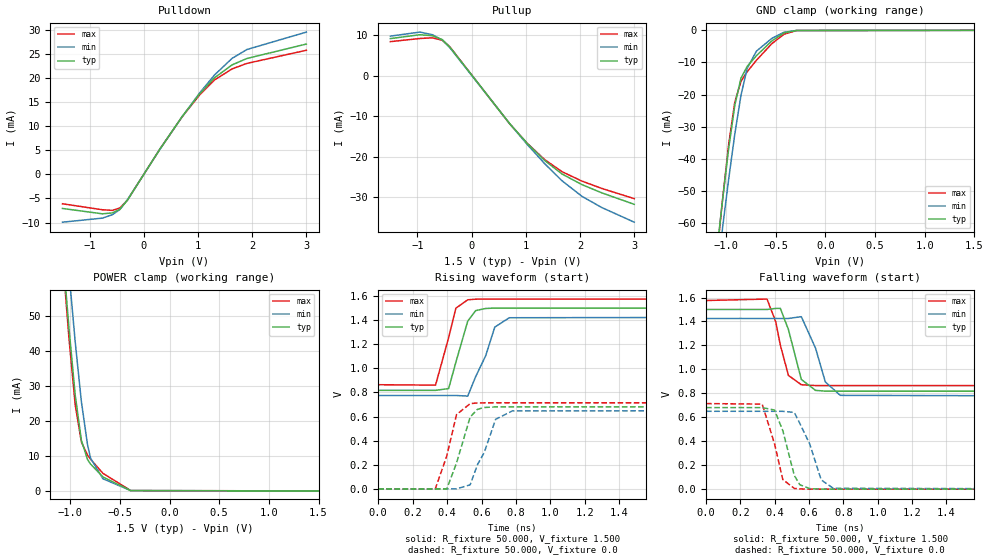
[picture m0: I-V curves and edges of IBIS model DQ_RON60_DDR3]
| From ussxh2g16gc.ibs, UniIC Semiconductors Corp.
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|   Model DQ_RON60_DDR3
[Model] DQ_RON60_DDR3
Model_type I/O
Vinl =  0.615V
Vinh =  0.885V
Vmeas =  0.750V
Rref =  50.000
Vref =  0.750V
C_comp   0.966pF   0.965pF   0.967pF
[Model Spec]
Vinh   0.885V   0.847V   0.922V
Vinl   0.615V   0.577V   0.652V
Vmeas   0.750V   0.712V   0.787V
Vref   0.750V   0.712V   0.787V
Rref   50.000   NA   NA
[Temperature Range]   25.000   95.000   0.0
[Voltage Range]   1.500V   1.425V   1.575V
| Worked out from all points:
|   slope of the pulldown table from 0 to 0.225 V, typ, clamps not added: 56.5 ohm
|   slope of the pullup table from 0 to 0.225 V, typ, clamps not added: 57.4 ohm
|   GND clamp passes 1 mA (typ) near -0.43 V on its own axis
|   POWER clamp passes 1 mA (typ) near -0.52 V on its own axis
|   rising waveform, R_fixture 50.000, V_fixture 1.500: 20-80 % time 81.6ps typ, 103ps min, 71ps max; typ from 0.818 V to 1.5 V
|   rising waveform, R_fixture 50.000, V_fixture 0.0: 20-80 % time 84.5ps typ, 106ps min, 74.9ps max; typ from 0 V to 0.681 V
|   falling waveform, R_fixture 50.000, V_fixture 1.500: 20-80 % time 71.8ps typ, 86.9ps min, 65.2ps max; typ from 1.5 V to 0.818 V
|   falling waveform, R_fixture 50.000, V_fixture 0.0: 20-80 % time 76.4ps typ, 97.3ps min, 66.7ps max; typ from 0.681 V to 0 V
[Pulldown]
|Voltage   I(typ)   I(min)   I(max)
-1.5V     -7.077mA   -9.924mA   -6.103mA
-764mV    -8.187mA   -9.081mA   -7.347mA
-580mV    -7.998mA   -8.377mA   -7.472mA
-442mV    -7.252mA   -7.298mA   -6.985mA
-304mV    -5.41mA    -5.318mA   -5.388mA
294mV     5.178mA    5.104mA    5.182mA
708mV     11.98mA    11.95mA    11.91mA
1.03V     16.67mA    16.85mA    16.45mA
1.306V    20.02mA    20.6mA     19.56mA
1.628V    22.68mA    24.03mA    21.85mA
1.904V    24.02mA    25.88mA    23mA
3V        27.01mA    29.49mA    25.72mA
[Pullup]
|Voltage   I(typ)   I(min)   I(max)
-1.5V     9.205mA    9.811mA    8.45mA
-956mV    10.16mA    10.81mA    9.228mA
-726mV    9.917mA    10.17mA    9.391mA
-542mV    8.946mA    8.844mA    8.795mA
-404mV    7.122mA    6.979mA    7.188mA
700mV     -11.77mA   -11.79mA   -11.84mA
1.022V    -16.63mA   -16.89mA   -16.61mA
1.344V    -20.88mA   -21.65mA   -20.65mA
1.666V    -24.23mA   -25.9mA    -23.66mA
2.034V    -26.86mA   -29.75mA   -25.99mA
2.402V    -28.9mA    -32.53mA   -27.81mA
3V        -31.73mA   -36.14mA   -30.33mA
[GND_clamp]
|Voltage   I(typ)   I(min)   I(max)
-1.5V     -194.2mA   -188.5mA   -209.3mA
-1.066V   -61.52mA   -69.48mA   -62.16mA
-1.035V   -52.91mA   -61.57mA   -52.74mA
-973mV    -36.75mA   -46.31mA   -35.46mA
-911mV    -23.25mA   -32.21mA   -22.31mA
-849mV    -14.87mA   -20.19mA   -15.86mA
-787mV    -11.24mA   -11.84mA   -12.89mA
-694mV    -7.909mA   -6.483mA   -9.328mA
-539mV    -3.3mA     -2.519mA   -4.154mA
-415mV    -796.6uA   -587.2uA   -1.2mA
-291mV    -42.28uA   -42.7uA    -83.65uA
1.5V      0A         0A         0A
[POWER_clamp]
|Voltage   I(typ)   I(min)   I(max)
-1.5V     238.9mA    243.4mA    249.4mA
-1.104V   79.29mA    94.04mA    78.24mA
-1.073V   67.84mA    83.12mA    66.04mA
-1.042V   56.75mA    72.44mA    54.3mA
-1.011V   46.15mA    62.05mA    43.22mA
-949mV    27.34mA    42.47mA    24.53mA
-887mV    14.41mA    25.48mA    13.98mA
-825mV    8.956mA    13.13mA    10.21mA
-794mV    7.645mA    9.305mA    9.033mA
-670mV    3.99mA     3.471mA    5.018mA
-391mV    72.25uA    105.7uA    112.3uA
1.5V      0A         0A         0A
[Ramp]
| variable   typ   min   max
dV/dt_r   0.409/84.474p   0.390/0.106n   0.429/74.925p
dV/dt_f   0.409/71.683p   0.390/86.888p   0.426/65.445p
R_load = 50.000
[Rising Waveform]
R_fixture= 50.000
V_fixture= 1.500
V_fixture_min= 1.425
V_fixture_max= 1.575
|time   V(typ)   V(min)   V(max)
0s        817.6mV    774.9mV    864.4mV
333ps     817.5mV    774.9mV    860.8mV
409ps     832.3mV    774.9mV    1.254V
451ps     1.05V      775.1mV    1.499V
520ps     1.392V     770.1mV    1.569V
566ps     1.479V     931.2mV    1.574V
624ps     1.497V     1.104V     1.575V
677ps     1.5V       1.342V     1.575V
761ps     1.5V       1.42V      1.575V
3ns       1.5V       1.425V     1.575V
[Rising Waveform]
R_fixture= 50.000
V_fixture= 0.0
V_fixture_min= 0.0
V_fixture_max= 0.0
|time   V(typ)   V(min)   V(max)
0s        223nV      1.468uV    252.9nV
331ps     -38.28uV   3.821uV    -2.24mV
398ps     -1.264mV   -6.258uV   271.9mV
455ps     214.8mV    185.2uV    616.7mV
534ps     596.1mV    33.9mV     707.6mV
577ps     660.6mV    202.4mV    712.9mV
616ps     675.4mV    302.3mV    714.1mV
682ps     680.4mV    577.5mV    714.5mV
779ps     681mV      646.9mV    714.5mV
3ns       681.1mV    650.1mV    714.5mV
[Falling Waveform]
R_fixture= 50.000
V_fixture= 1.500
V_fixture_min= 1.425
V_fixture_max= 1.575
|time   V(typ)   V(min)   V(max)
0s        1.5V       1.425V     1.575V
355ps     1.5V       1.425V     1.587V
406ps     1.509V     1.425V     1.397V
433ps     1.509V     1.425V     1.201V
480ps     1.332V     1.425V     949.6mV
555ps     916.2mV    1.44V      871.9mV
638ps     824.6mV    1.177V     864.9mV
695ps     818.6mV    895.4mV    864.5mV
782ps     817.6mV    783.2mV    864.4mV
3ns       817.6mV    774.9mV    864.4mV
[Falling Waveform]
R_fixture= 50.000
V_fixture= 0.0
V_fixture_min= 0.0
V_fixture_max= 0.0
|time   V(typ)   V(min)   V(max)
0s        681.1mV    650.1mV    714.5mV
327ps     681mV      650mV      710.1mV
399ps     660.4mV    650mV      378.5mV
447ps     489.2mV    649.9mV    80.81mV
514ps     115mV      640.8mV    6.568mV
546ps     37.14mV    550mV      1.974mV
604ps     4.596mV    377mV      213.9uV
671ps     405.4uV    77.49mV    16.47uV
741ps     30.4uV     7.48mV     1.411uV
3ns       258.2nV    1.483uV    307.7nV
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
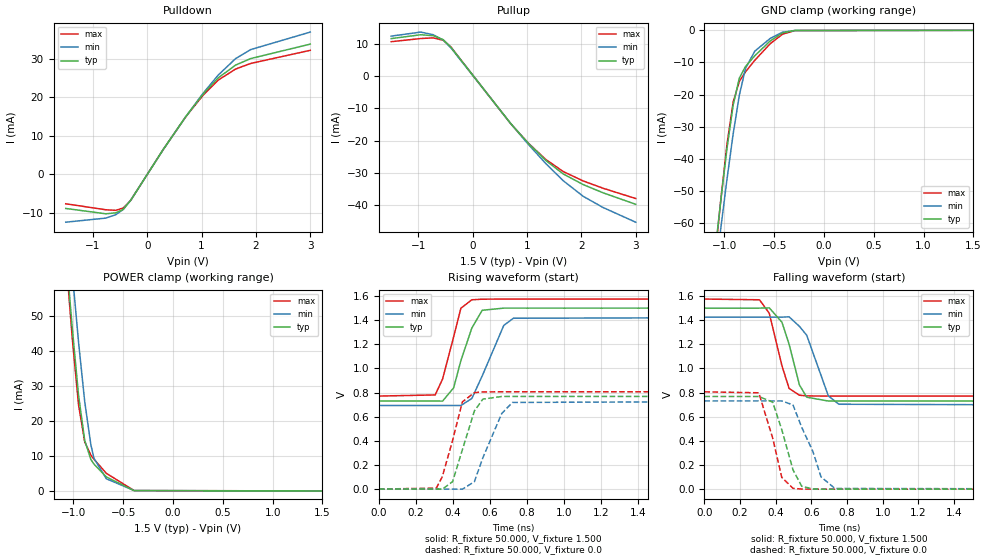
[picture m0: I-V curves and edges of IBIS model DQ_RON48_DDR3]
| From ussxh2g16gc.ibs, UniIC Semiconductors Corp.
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|   Model DQ_RON48_DDR3
[Model] DQ_RON48_DDR3
Model_type I/O
Vinl =  0.615V
Vinh =  0.885V
Vmeas =  0.750V
Rref =  50.000
Vref =  0.750V
C_comp   0.966pF   0.965pF   0.967pF
[Model Spec]
Vinh   0.885V   0.847V   0.922V
Vinl   0.615V   0.577V   0.652V
Vmeas   0.750V   0.712V   0.787V
Vref   0.750V   0.712V   0.787V
Rref   50.000   NA   NA
[Temperature Range]   25.000   95.000   0.0
[Voltage Range]   1.500V   1.425V   1.575V
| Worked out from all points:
|   slope of the pulldown table from 0 to 0.225 V, typ, clamps not added: 45.2 ohm
|   slope of the pullup table from 0 to 0.225 V, typ, clamps not added: 45.9 ohm
|   GND clamp passes 1 mA (typ) near -0.43 V on its own axis
|   POWER clamp passes 1 mA (typ) near -0.52 V on its own axis
|   rising waveform, R_fixture 50.000, V_fixture 1.500: 20-80 % time 90ps typ, 117ps min, 77.5ps max; typ from 0.73 V to 1.5 V
|   rising waveform, R_fixture 50.000, V_fixture 0.0: 20-80 % time 91.1ps typ, 115ps min, 80.3ps max; typ from 0 V to 0.768 V
|   falling waveform, R_fixture 50.000, V_fixture 1.500: 20-80 % time 83.9ps typ, 104ps min, 75.5ps max; typ from 1.5 V to 0.73 V
|   falling waveform, R_fixture 50.000, V_fixture 0.0: 20-80 % time 90.1ps typ, 114ps min, 78.3ps max; typ from 0.768 V to 0 V
[Pulldown]
|Voltage   I(typ)   I(min)   I(max)
-1.5V     -8.855mA   -12.42mA   -7.638mA
-764mV    -10.24mA   -11.36mA   -9.193mA
-580mV    -10mA      -10.48mA   -9.347mA
-442mV    -9.069mA   -9.126mA   -8.736mA
-304mV    -6.766mA   -6.65mA    -6.738mA
294mV     6.475mA    6.383mA    6.481mA
708mV     14.98mA    14.94mA    14.9mA
1.03V     20.85mA    21.08mA    20.57mA
1.306V    25.04mA    25.76mA    24.46mA
1.628V    28.37mA    30.06mA    27.34mA
1.904V    30.05mA    32.38mA    28.78mA
3V        33.8mA     36.92mA    32.19mA
[Pullup]
|Voltage   I(typ)   I(min)   I(max)
-1.5V     11.52mA    12.28mA    10.56mA
-956mV    12.71mA    13.53mA    11.54mA
-726mV    12.41mA    12.72mA    11.74mA
-542mV    11.19mA    11.06mA    11mA
-404mV    8.909mA    8.73mA     8.986mA
700mV     -14.73mA   -14.75mA   -14.8mA
1.022V    -20.8mA    -21.12mA   -20.76mA
1.344V    -26.12mA   -27.08mA   -25.81mA
1.666V    -30.31mA   -32.4mA    -29.57mA
2.034V    -33.61mA   -37.23mA   -32.48mA
2.402V    -36.16mA   -40.71mA   -34.75mA
3V        -39.7mA    -45.23mA   -37.91mA
[GND_clamp]
|Voltage   I(typ)   I(min)   I(max)
-1.5V     -194.2mA   -188.5mA   -209.3mA
-1.066V   -61.52mA   -69.48mA   -62.16mA
-1.035V   -52.91mA   -61.57mA   -52.74mA
-973mV    -36.75mA   -46.31mA   -35.46mA
-911mV    -23.25mA   -32.21mA   -22.31mA
-849mV    -14.87mA   -20.19mA   -15.86mA
-787mV    -11.24mA   -11.84mA   -12.89mA
-694mV    -7.909mA   -6.483mA   -9.328mA
-539mV    -3.3mA     -2.519mA   -4.154mA
-415mV    -796.6uA   -587.2uA   -1.2mA
-291mV    -42.28uA   -42.7uA    -83.65uA
1.5V      0A         0A         0A
[POWER_clamp]
|Voltage   I(typ)   I(min)   I(max)
-1.5V     238.9mA    243.4mA    249.4mA
-1.104V   79.29mA    94.04mA    78.24mA
-1.073V   67.84mA    83.12mA    66.04mA
-1.042V   56.75mA    72.44mA    54.3mA
-1.011V   46.15mA    62.05mA    43.22mA
-949mV    27.34mA    42.47mA    24.53mA
-887mV    14.41mA    25.48mA    13.98mA
-825mV    8.956mA    13.13mA    10.21mA
-794mV    7.645mA    9.305mA    9.033mA
-670mV    3.99mA     3.471mA    5.018mA
-391mV    72.25uA    105.7uA    112.3uA
1.5V      0A         0A         0A
[Ramp]
| variable   typ   min   max
dV/dt_r   0.461/90.981p   0.439/0.115n   0.484/80.401p
dV/dt_f   0.462/83.868p   0.439/0.104n   0.482/75.519p
R_load = 50.000
[Rising Waveform]
R_fixture= 50.000
V_fixture= 1.500
V_fixture_min= 1.425
V_fixture_max= 1.575
|time   V(typ)   V(min)   V(max)
0s        729.8mV    693mV      771mV
304ps     729.8mV    693mV      780.3mV
344ps     729.1mV    693mV      912.4mV
404ps     839.9mV    693mV      1.263V
443ps     1.065V     692.6mV    1.499V
502ps     1.334V     750.7mV    1.569V
558ps     1.482V     937mV      1.574V
675ps     1.5V       1.357V     1.575V
727ps     1.5V       1.416V     1.575V
3ns       1.5V       1.425V     1.575V
[Rising Waveform]
R_fixture= 50.000
V_fixture= 0.0
V_fixture_min= 0.0
V_fixture_max= 0.0
|time   V(typ)   V(min)   V(max)
0s        208.5nV    1.321uV    242.4nV
310ps     62.31uV    5.681uV    8.055mV
342ps     -657.9uV   1.334uV    100.5mV
398ps     60.93mV    18.37uV    402.5mV
451ps     326mV      -727.6uV   723.3mV
516ps     647.3mV    61.34mV    799.4mV
562ps     745.7mV    260.6mV    805.2mV
664ps     767.4mV    626.9mV    806.5mV
722ps     767.9mV    718.1mV    806.5mV
3ns       767.9mV    731.2mV    806.5mV
[Falling Waveform]
R_fixture= 50.000
V_fixture= 1.500
V_fixture_min= 1.425
V_fixture_max= 1.575
|time   V(typ)   V(min)   V(max)
0s        1.5V       1.425V     1.575V
309ps     1.5V       1.425V     1.569V
364ps     1.502V     1.425V     1.457V
435ps     1.383V     1.425V     1.022V
475ps     1.201V     1.428V     834.8mV
533ps     863.9mV    1.349V     778.5mV
574ps     762mV      1.275V     772.6mV
695ps     730.2mV    772.9mV    771mV
754ps     729.9mV    703.6mV    771mV
3ns       729.8mV    693mV      771mV
[Falling Waveform]
R_fixture= 50.000
V_fixture= 0.0
V_fixture_min= 0.0
V_fixture_max= 0.0
|time   V(typ)   V(min)   V(max)
0s        767.9mV    731.2mV    806.5mV
305ps     767.8mV    731.2mV    798.4mV
383ps     721.1mV    731.2mV    423.3mV
434ps     493.2mV    731.1mV    97.5mV
497ps     159.9mV    697.6mV    6.883mV
546ps     23.8mV     511.8mV    853.2uV
609ps     1.846mV    310.2mV    55.42uV
654ps     294.6uV    102mV      8.177uV
732ps     11.67uV    5.786mV    632.1nV
3ns       217.6nV    1.311uV    319.8nV
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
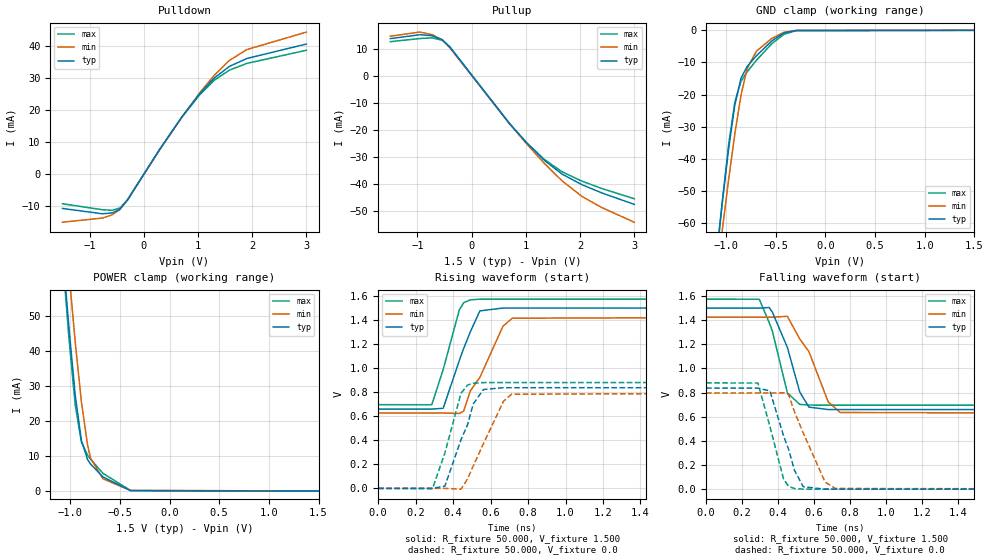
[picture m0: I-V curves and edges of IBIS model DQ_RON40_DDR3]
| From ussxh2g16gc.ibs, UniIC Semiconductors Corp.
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|   Model DQ_RON40_DDR3
[Model] DQ_RON40_DDR3
Model_type I/O
Vinl =  0.615V
Vinh =  0.885V
Vmeas =  0.750V
Rref =  50.000
Vref =  0.750V
C_comp   0.966pF   0.965pF   0.967pF
[Model Spec]
Vinh   0.885V   0.847V   0.922V
Vinl   0.615V   0.577V   0.652V
Vmeas   0.750V   0.712V   0.787V
Vref   0.750V   0.712V   0.787V
Rref   50.000   NA   NA
[Temperature Range]   25.000   95.000   0.0
[Voltage Range]   1.500V   1.425V   1.575V
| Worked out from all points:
|   slope of the pulldown table from 0 to 0.225 V, typ, clamps not added: 37.7 ohm
|   slope of the pullup table from 0 to 0.225 V, typ, clamps not added: 38.3 ohm
|   GND clamp passes 1 mA (typ) near -0.43 V on its own axis
|   POWER clamp passes 1 mA (typ) near -0.52 V on its own axis
|   rising waveform, R_fixture 50.000, V_fixture 1.500: 20-80 % time 119ps typ, 161ps min, 98.6ps max; typ from 0.659 V to 1.5 V
|   rising waveform, R_fixture 50.000, V_fixture 0.0: 20-80 % time 109ps typ, 148ps min, 89.9ps max; typ from 0 V to 0.837 V
|   falling waveform, R_fixture 50.000, V_fixture 1.500: 20-80 % time 112ps typ, 151ps min, 92.4ps max; typ from 1.5 V to 0.659 V
|   falling waveform, R_fixture 50.000, V_fixture 0.0: 20-80 % time 107ps typ, 141ps min, 91.1ps max; typ from 0.837 V to 0 V
[Pulldown]
|Voltage   I(typ)   I(min)   I(max)
-1.5V     -10.61mA   -14.88mA   -9.148mA
-764mV    -12.27mA   -13.61mA   -11.01mA
-580mV    -11.99mA   -12.56mA   -11.2mA
-442mV    -10.87mA   -10.94mA   -10.47mA
-304mV    -8.107mA   -7.968mA   -8.072mA
294mV     7.758mA    7.648mA    7.763mA
708mV     17.95mA    17.9mA     17.85mA
1.03V     24.98mA    25.25mA    24.65mA
1.306V    30mA       30.86mA    29.3mA
1.582V    33.55mA    35.4mA     32.38mA
1.904V    35.99mA    38.77mA    34.47mA
3V        40.48mA    44.19mA    38.54mA
[Pullup]
|Voltage   I(typ)   I(min)   I(max)
-1.5V     13.8mA     14.7mA     12.67mA
-956mV    15.23mA    16.21mA    13.83mA
-726mV    14.86mA    15.24mA    14.08mA
-542mV    13.41mA    13.25mA    13.18mA
-404mV    10.67mA    10.46mA    10.77mA
700mV     -17.64mA   -17.67mA   -17.74mA
1.022V    -24.91mA   -25.3mA    -24.88mA
1.344V    -31.28mA   -32.43mA   -30.93mA
1.666V    -36.29mA   -38.79mA   -35.44mA
2.034V    -40.23mA   -44.56mA   -38.92mA
2.402V    -43.28mA   -48.71mA   -41.65mA
3V        -47.51mA   -54.1mA    -45.43mA
[GND_clamp]
|Voltage   I(typ)   I(min)   I(max)
-1.5V     -194.2mA   -188.5mA   -209.3mA
-1.066V   -61.52mA   -69.48mA   -62.16mA
-1.035V   -52.91mA   -61.57mA   -52.74mA
-973mV    -36.75mA   -46.31mA   -35.46mA
-911mV    -23.25mA   -32.21mA   -22.31mA
-849mV    -14.87mA   -20.19mA   -15.86mA
-787mV    -11.24mA   -11.84mA   -12.89mA
-694mV    -7.909mA   -6.483mA   -9.328mA
-539mV    -3.3mA     -2.519mA   -4.154mA
-415mV    -796.6uA   -587.2uA   -1.2mA
-291mV    -42.28uA   -42.7uA    -83.65uA
1.5V      0A         0A         0A
[POWER_clamp]
|Voltage   I(typ)   I(min)   I(max)
-1.5V     238.9mA    243.4mA    249.4mA
-1.104V   79.29mA    94.04mA    78.24mA
-1.073V   67.84mA    83.12mA    66.04mA
-1.042V   56.75mA    72.44mA    54.3mA
-1.011V   46.15mA    62.05mA    43.22mA
-949mV    27.34mA    42.47mA    24.53mA
-887mV    14.41mA    25.48mA    13.98mA
-825mV    8.956mA    13.13mA    10.21mA
-794mV    7.645mA    9.305mA    9.033mA
-670mV    3.99mA     3.471mA    5.018mA
-391mV    72.25uA    105.7uA    112.3uA
1.5V      0A         0A         0A
[Ramp]
| variable   typ   min   max
dV/dt_r   0.502/0.108n   0.478/0.148n   0.528/89.963p
dV/dt_f   0.504/0.112n   0.479/0.151n   0.527/92.509p
R_load = 50.000
[Rising Waveform]
R_fixture= 50.000
V_fixture= 1.500
V_fixture_min= 1.425
V_fixture_max= 1.575
|time   V(typ)   V(min)   V(max)
0s        659.5mV    627.1mV    696.2mV
286ps     659.5mV    627.1mV    695.9mV
347ps     666.4mV    627.1mV    989.2mV
433ps     1.064V     623mV      1.485V
456ps     1.163V     642.3mV    1.544V
492ps     1.303V     811.2mV    1.569V
543ps     1.477V     924.1mV    1.574V
666ps     1.5V       1.349V     1.575V
716ps     1.5V       1.416V     1.575V
3ns       1.5V       1.425V     1.575V
[Rising Waveform]
R_fixture= 50.000
V_fixture= 0.0
V_fixture_min= 0.0
V_fixture_max= 0.0
|time   V(typ)   V(min)   V(max)
0s        197.4nV    1.203uV    234.8nV
290ps     75.71uV    3.746uV    -1.937mV
356ps     18.73mV    -53.76uV   294.2mV
442ps     404.8mV    -6.628mV   791.4mV
477ps     529.5mV    78.62mV    859.6mV
507ps     701.2mV    185mV      874.5mV
562ps     822.6mV    372.6mV    879.9mV
669ps     837.3mV    725.3mV    880.5mV
712ps     837.4mV    783.4mV    880.5mV
3ns       837.4mV    796.3mV    880.5mV
[Falling Waveform]
R_fixture= 50.000
V_fixture= 1.500
V_fixture_min= 1.425
V_fixture_max= 1.575
|time   V(typ)   V(min)   V(max)
0s        1.5V       1.425V     1.575V
296ps     1.5V       1.425V     1.573V
351ps     1.505V     1.425V     1.38V
369ps     1.465V     1.425V     1.307V
452ps     1.174V     1.432V     797mV
521ps     804.1mV    1.244V     702.5mV
572ps     679.7mV    1.139V     697mV
679ps     659.7mV    722.9mV    696.2mV
746ps     659.5mV    635.2mV    696.2mV
3ns       659.5mV    627.1mV    696.2mV
[Falling Waveform]
R_fixture= 50.000
V_fixture= 0.0
V_fixture_min= 0.0
V_fixture_max= 0.0
|time   V(typ)   V(min)   V(max)
0s        837.4mV    796.3mV    880.5mV
288ps     837.3mV    796.3mV    879.5mV
355ps     813.9mV    796.3mV    518.4mV
431ps     440.7mV    797.8mV    83.25mV
459ps     329.6mV    783.9mV    23.17mV
491ps     158.4mV    642.5mV    5.125mV
540ps     19.92mV    466.5mV    518.5uV
662ps     87.94uV    58.13mV    1.85uV
720ps     6.634uV    5.563mV    438.5nV
3ns       226.3nV    1.164uV    278.6nV
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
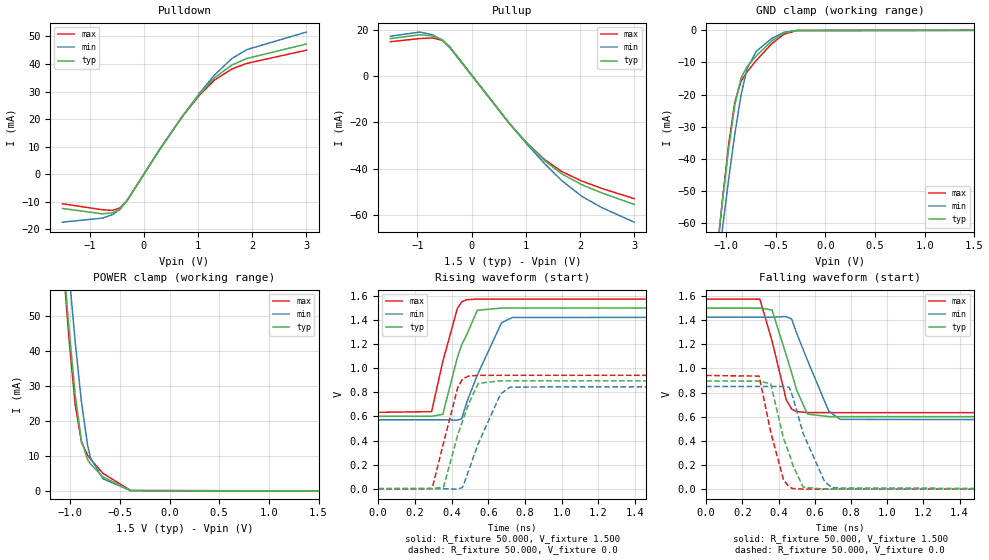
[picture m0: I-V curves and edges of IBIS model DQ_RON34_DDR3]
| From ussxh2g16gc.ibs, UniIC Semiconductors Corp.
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|   Model DQ_RON34_DDR3
[Model] DQ_RON34_DDR3
Model_type I/O
Vinl =  0.615V
Vinh =  0.885V
Vmeas =  0.750V
Rref =  50.000
Vref =  0.750V
C_comp   0.966pF   0.965pF   0.967pF
[Model Spec]
Vinh   0.885V   0.847V   0.922V
Vinl   0.615V   0.577V   0.652V
Vmeas   0.750V   0.712V   0.787V
Vref   0.750V   0.712V   0.787V
Rref   50.000   NA   NA
[Temperature Range]   25.000   95.000   0.0
[Voltage Range]   1.500V   1.425V   1.575V
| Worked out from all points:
|   slope of the pulldown table from 0 to 0.225 V, typ, clamps not added: 32.3 ohm
|   slope of the pullup table from 0 to 0.225 V, typ, clamps not added: 32.8 ohm
|   GND clamp passes 1 mA (typ) near -0.43 V on its own axis
|   POWER clamp passes 1 mA (typ) near -0.52 V on its own axis
|   rising waveform, R_fixture 50.000, V_fixture 1.500: 20-80 % time 114ps typ, 151ps min, 95.9ps max; typ from 0.601 V to 1.5 V
|   rising waveform, R_fixture 50.000, V_fixture 0.0: 20-80 % time 108ps typ, 142ps min, 91.5ps max; typ from 0 V to 0.896 V
|   falling waveform, R_fixture 50.000, V_fixture 1.500: 20-80 % time 111ps typ, 145ps min, 95.3ps max; typ from 1.5 V to 0.601 V
|   falling waveform, R_fixture 50.000, V_fixture 0.0: 20-80 % time 102ps typ, 132ps min, 88.3ps max; typ from 0.896 V to 0 V
[Pulldown]
|Voltage   I(typ)   I(min)   I(max)
-1.5V     -12.39mA   -17.36mA   -10.68mA
-764mV    -14.32mA   -15.88mA   -12.85mA
-580mV    -13.99mA   -14.65mA   -13.07mA
-442mV    -12.68mA   -12.76mA   -12.21mA
-304mV    -9.452mA   -9.291mA   -9.412mA
294mV     9.046mA    8.917mA    9.052mA
708mV     20.93mA    20.87mA    20.81mA
1.03V     29.13mA    29.45mA    28.74mA
1.306V    34.98mA    35.99mA    34.17mA
1.628V    39.63mA    41.99mA    38.19mA
1.904V    41.98mA    45.21mA    40.21mA
3V        47.22mA    51.54mA    44.96mA
[Pullup]
|Voltage   I(typ)   I(min)   I(max)
-1.5V     16.11mA    17.15mA    14.78mA
-956mV    17.77mA    18.93mA    16.14mA
-726mV    17.35mA    17.79mA    16.42mA
-542mV    15.64mA    15.46mA    15.37mA
-404mV    12.45mA    12.2mA     12.56mA
700mV     -20.57mA   -20.61mA   -20.68mA
1.022V    -29.06mA   -29.51mA   -29.01mA
1.344V    -36.49mA   -37.83mA   -36.06mA
1.666V    -42.33mA   -45.25mA   -41.31mA
2.034V    -46.94mA   -51.98mA   -45.37mA
2.402V    -50.49mA   -56.83mA   -48.55mA
3V        -55.43mA   -63.11mA   -52.95mA
[GND_clamp]
|Voltage   I(typ)   I(min)   I(max)
-1.5V     -194.2mA   -188.5mA   -209.3mA
-1.066V   -61.52mA   -69.48mA   -62.16mA
-1.035V   -52.91mA   -61.57mA   -52.74mA
-973mV    -36.75mA   -46.31mA   -35.46mA
-911mV    -23.25mA   -32.21mA   -22.31mA
-849mV    -14.87mA   -20.19mA   -15.86mA
-787mV    -11.24mA   -11.84mA   -12.89mA
-694mV    -7.909mA   -6.483mA   -9.328mA
-539mV    -3.3mA     -2.519mA   -4.154mA
-415mV    -796.6uA   -587.2uA   -1.2mA
-291mV    -42.28uA   -42.7uA    -83.65uA
1.5V      0A         0A         0A
[POWER_clamp]
|Voltage   I(typ)   I(min)   I(max)
-1.5V     238.9mA    243.4mA    249.4mA
-1.104V   79.29mA    94.04mA    78.24mA
-1.073V   67.84mA    83.12mA    66.04mA
-1.042V   56.75mA    72.44mA    54.3mA
-1.011V   46.15mA    62.05mA    43.22mA
-949mV    27.34mA    42.47mA    24.53mA
-887mV    14.41mA    25.48mA    13.98mA
-825mV    8.956mA    13.13mA    10.21mA
-794mV    7.645mA    9.305mA    9.033mA
-670mV    3.99mA     3.471mA    5.018mA
-391mV    72.25uA    105.7uA    112.3uA
1.5V      0A         0A         0A
[Ramp]
| variable   typ   min   max
dV/dt_r   0.537/0.108n   0.510/0.142n   0.565/91.452p
dV/dt_f   0.539/0.111n   0.512/0.145n   0.565/95.483p
R_load = 50.000
[Rising Waveform]
R_fixture= 50.000
V_fixture= 1.500
V_fixture_min= 1.425
V_fixture_max= 1.575
|time   V(typ)   V(min)   V(max)
0s        601.1mV    572.4mV    634.1mV
291ps     601.2mV    572.5mV    640mV
352ps     617.7mV    572.4mV    1.056V
431ps     1.086V     569.2mV    1.495V
455ps     1.195V     580mV      1.552V
484ps     1.284V     724.4mV    1.57V
540ps     1.482V     942.2mV    1.575V
672ps     1.5V       1.378V     1.575V
731ps     1.5V       1.422V     1.575V
3ns       1.5V       1.425V     1.575V
[Rising Waveform]
R_fixture= 50.000
V_fixture= 0.0
V_fixture_min= 0.0
V_fixture_max= 0.0
|time   V(typ)   V(min)   V(max)
0s        187.9nV    1.105uV    228nV
294ps     143.6uV    5.374uV    1.426mV
356ps     13.75mV    -62.73uV   378.2mV
434ps     449mV      -4.096mV   842.3mV
460ps     562.2mV    11.22mV    911.5mV
494ps     708.3mV    155mV      935.5mV
546ps     875.3mV    377.4mV    941.3mV
667ps     895.5mV    787.1mV    941.9mV
719ps     895.6mV    844.2mV    941.9mV
3ns       895.6mV    850.7mV    941.9mV
[Falling Waveform]
R_fixture= 50.000
V_fixture= 1.500
V_fixture_min= 1.425
V_fixture_max= 1.575
|time   V(typ)   V(min)   V(max)
0s        1.5V       1.425V     1.575V
297ps     1.5V       1.425V     1.574V
364ps     1.485V     1.425V     1.229V
443ps     1.109V     1.43V      739.4mV
473ps     960.7mV    1.409V     663mV
500ps     821.7mV    1.292V     642.6mV
560ps     622mV      1.067V     634.7mV
678ps     601.2mV    645.3mV    634.1mV
741ps     601.1mV    578.3mV    634.1mV
3ns       601.1mV    572.4mV    634.1mV
[Falling Waveform]
R_fixture= 50.000
V_fixture= 0.0
V_fixture_min= 0.0
V_fixture_max= 0.0
|time   V(typ)   V(min)   V(max)
0s        895.6mV    850.7mV    941.9mV
293ps     895.3mV    850.7mV    936.7mV
357ps     873.1mV    850.7mV    473.9mV
427ps     424mV      851.4mV    79.85mV
459ps     294.4mV    844.1mV    15.74mV
480ps     195mV      759.6mV    5.508mV
536ps     16.81mV    462.5mV    316.3uV
654ps     57.75uV    63.91mV    1.128uV
697ps     7.75uV     9.89mV     417.7nV
3ns       165.2nV    1.074uV    228.6nV
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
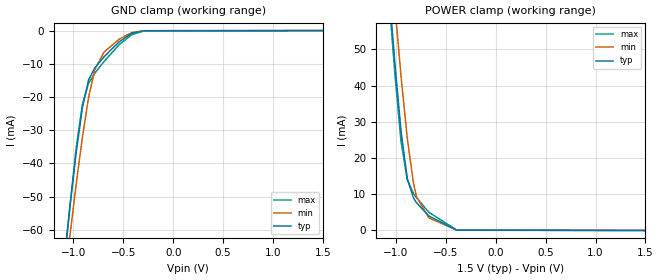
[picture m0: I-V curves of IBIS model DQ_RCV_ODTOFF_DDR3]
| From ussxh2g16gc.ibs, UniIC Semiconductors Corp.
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|   Model DQ_RCV_ODTOFF_DDR3
[Model] DQ_RCV_ODTOFF_DDR3
Model_type Input
Vinl =  0.615V
Vinh =  0.885V
C_comp   0.966pF   0.965pF   0.967pF
[Model Spec]
Vinh   0.885V   0.847V   0.922V
Vinl   0.615V   0.577V   0.652V
[Temperature Range]   25.000   95.000   0.0
[Voltage Range]   1.500V   1.425V   1.575V
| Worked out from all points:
|   GND clamp passes 1 mA (typ) near -0.43 V on its own axis
|   POWER clamp passes 1 mA (typ) near -0.52 V on its own axis
[GND_clamp]
|Voltage   I(typ)   I(min)   I(max)
-1.5V     -194.2mA   -188.5mA   -209.3mA
-1.066V   -61.52mA   -69.48mA   -62.16mA
-1.035V   -52.91mA   -61.57mA   -52.74mA
-973mV    -36.75mA   -46.31mA   -35.46mA
-911mV    -23.25mA   -32.21mA   -22.31mA
-849mV    -14.87mA   -20.19mA   -15.86mA
-787mV    -11.24mA   -11.84mA   -12.89mA
-694mV    -7.909mA   -6.483mA   -9.328mA
-539mV    -3.3mA     -2.519mA   -4.154mA
-415mV    -796.6uA   -587.2uA   -1.2mA
-291mV    -42.28uA   -42.7uA    -83.65uA
1.5V      0A         0A         0A
[POWER_clamp]
|Voltage   I(typ)   I(min)   I(max)
-1.5V     238.9mA    243.4mA    249.4mA
-1.104V   79.29mA    94.04mA    78.24mA
-1.073V   67.84mA    83.12mA    66.04mA
-1.042V   56.75mA    72.44mA    54.3mA
-1.011V   46.15mA    62.05mA    43.22mA
-949mV    27.34mA    42.47mA    24.53mA
-887mV    14.41mA    25.48mA    13.98mA
-825mV    8.956mA    13.13mA    10.21mA
-794mV    7.645mA    9.305mA    9.033mA
-670mV    3.99mA     3.471mA    5.018mA
-391mV    72.25uA    105.7uA    112.3uA
1.5V      0A         0A         0A
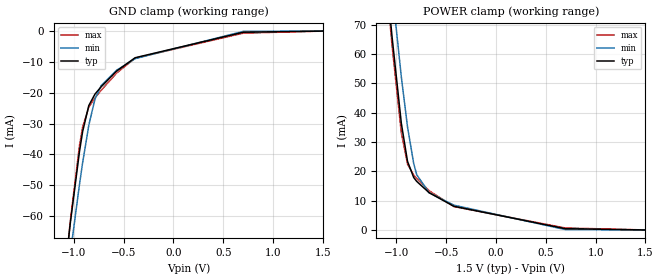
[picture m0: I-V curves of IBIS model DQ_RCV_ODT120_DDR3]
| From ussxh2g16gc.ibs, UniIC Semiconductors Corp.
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|   Model DQ_RCV_ODT120_DDR3
[Model] DQ_RCV_ODT120_DDR3
Model_type Input
Vinl =  0.615V
Vinh =  0.885V
C_comp   0.966pF   0.965pF   0.967pF
[Model Spec]
Vinh   0.885V   0.847V   0.922V
Vinl   0.615V   0.577V   0.652V
[Temperature Range]   25.000   95.000   0.0
[Voltage Range]   1.500V   1.425V   1.575V
[GND_clamp]
|Voltage   I(typ)   I(min)   I(max)
-1.5V     -204mA     -200mA     -218.5mA
-1.221V   -116.7mA   -121.8mA   -121.7mA
-1.035V   -62.34mA   -72.28mA   -61.65mA
-942mV    -38.88mA   -49.59mA   -36.99mA
-911mV    -32.58mA   -42.66mA   -31.14mA
-849mV    -24.13mA   -30.5mA    -24.66mA
-787mV    -20.42mA   -22.01mA   -21.65mA
-725mV    -18.05mA   -17.67mA   -19.19mA
-570mV    -12.95mA   -12.69mA   -13.62mA
-384mV    -8.642mA   -8.928mA   -8.768mA
701mV     -368.9uA   -91.38uA   -666.3uA
1.5V      0A         0A         0A
[POWER_clamp]
|Voltage   I(typ)   I(min)   I(max)
-1.5V     248mA      253.3mA    258mA
-1.104V   88.4mA     103.9mA    86.79mA
-1.073V   76.94mA    92.95mA    74.58mA
-1.042V   65.83mA    82.25mA    62.84mA
-949mV    36.37mA    52.19mA    33.06mA
-887mV    23.4mA     35.12mA    22.49mA
-825mV    17.89mA    22.68mA    18.7mA
-794mV    16.54mA    18.8mA     17.51mA
-670mV    12.71mA    12.7mA     13.39mA
-422mV    8.08mA     8.46mA     7.978mA
694mV     446.4uA    150.6uA    684.9uA
1.5V      0A         0A         0A
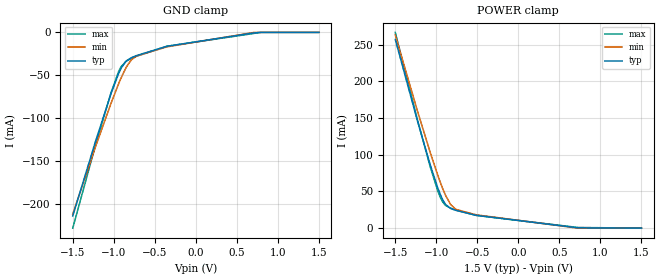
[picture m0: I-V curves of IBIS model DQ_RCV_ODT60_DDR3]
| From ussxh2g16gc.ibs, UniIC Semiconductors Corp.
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|   Model DQ_RCV_ODT60_DDR3
[Model] DQ_RCV_ODT60_DDR3
Model_type Input
Vinl =  0.615V
Vinh =  0.885V
C_comp   0.966pF   0.965pF   0.967pF
[Model Spec]
Vinh   0.885V   0.847V   0.922V
Vinl   0.615V   0.577V   0.652V
[Temperature Range]   25.000   95.000   0.0
[Voltage Range]   1.500V   1.425V   1.575V
[GND_clamp]
|Voltage   I(typ)   I(min)   I(max)
-1.5V     -213.6mA   -211.3mA   -227.7mA
-1.221V   -126.2mA   -132.6mA   -130.7mA
-1.035V   -71.63mA   -82.83mA   -70.51mA
-942mV    -48.1mA    -59.96mA   -45.8mA
-911mV    -41.77mA   -52.96mA   -39.93mA
-849mV    -33.26mA   -40.67mA   -33.42mA
-787mV    -29.49mA   -32.03mA   -30.37mA
-725mV    -27.04mA   -27.54mA   -27.86mA
-353mV    -16.18mA   -16.85mA   -16.17mA
701mV     -718.2uA   -167.7uA   -1.338mA
794mV     0A         0A         0A
1.5V      0A         0A         0A
[POWER_clamp]
|Voltage   I(typ)   I(min)   I(max)
-1.5V     257mA      263mA      266.6mA
-1.228V   145.5mA    159mA      146.8mA
-1.073V   85.93mA    102.7mA    83.06mA
-980mV    54.24mA    71.4mA     50.12mA
-949mV    45.29mA    61.79mA    41.51mA
-918mV    37.81mA    52.79mA    35.02mA
-887mV    32.28mA    44.65mA    30.93mA
-825mV    26.72mA    32.11mA    27.12mA
-763mV    24.23mA    25.62mA    24.8mA
-515mV    17.45mA    18.16mA    17.37mA
725mV     426.2uA    0A         894.5uA
1.5V      0A         0A         0A
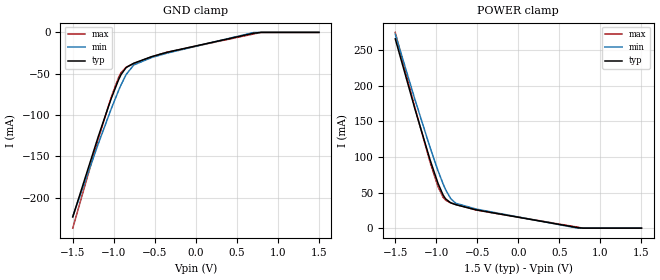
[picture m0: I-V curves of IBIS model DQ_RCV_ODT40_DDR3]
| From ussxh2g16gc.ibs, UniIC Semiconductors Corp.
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|   Model DQ_RCV_ODT40_DDR3
[Model] DQ_RCV_ODT40_DDR3
Model_type Input
Vinl =  0.615V
Vinh =  0.885V
C_comp   0.966pF   0.965pF   0.967pF
[Model Spec]
Vinh   0.885V   0.847V   0.922V
Vinl   0.615V   0.577V   0.652V
[Temperature Range]   25.000   95.000   0.0
[Voltage Range]   1.500V   1.425V   1.575V
[GND_clamp]
|Voltage   I(typ)   I(min)   I(max)
-1.5V     -223.3mA   -222.7mA   -236.8mA
-1.19V    -126.3mA   -135mA     -129.2mA
-1.035V   -81mA      -93.46mA   -79.36mA
-942mV    -57.39mA   -70.4mA    -54.6mA
-911mV    -51.03mA   -63.34mA   -48.71mA
-849mV    -42.46mA   -50.92mA   -42.16mA
-756mV    -37.3mA    -39.39mA   -37.77mA
-539mV    -29.38mA   -30.47mA   -29.5mA
-353mV    -24.16mA   -25.18mA   -24.01mA
701mV     -1.089mA   -264.2uA   -2.005mA
794mV     0A         0A         0A
1.5V      0A         0A         0A
[POWER_clamp]
|Voltage   I(typ)   I(min)   I(max)
-1.5V     266.1mA    272.8mA    275.2mA
-1.259V   167mA      180.4mA    168.7mA
-1.073V   94.97mA    112.4mA    91.56mA
-980mV    63.23mA    81.08mA    58.6mA
-918mV    46.77mA    62.4mA     43.49mA
-887mV    41.21mA    54.22mA    39.39mA
-825mV    35.59mA    41.59mA    35.56mA
-763mV    33.04mA    34.98mA    33.21mA
-515mV    25.72mA    26.81mA    25.4mA
725mV     626.6uA    0A         1.339mA
787mV     0A         0A         0A
1.5V      0A         0A         0A
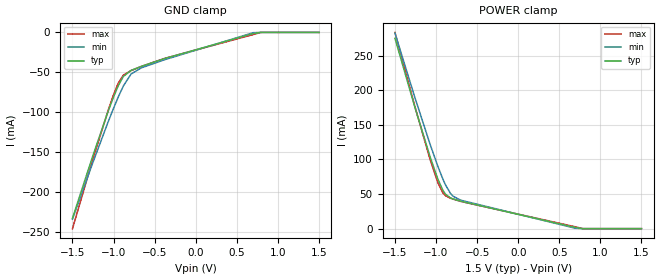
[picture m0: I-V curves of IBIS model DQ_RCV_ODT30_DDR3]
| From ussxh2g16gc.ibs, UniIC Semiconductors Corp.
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|   Model DQ_RCV_ODT30_DDR3
[Model] DQ_RCV_ODT30_DDR3
Model_type Input
Vinl =  0.615V
Vinh =  0.885V
C_comp   0.966pF   0.965pF   0.967pF
[Model Spec]
Vinh   0.885V   0.847V   0.922V
Vinl   0.615V   0.577V   0.652V
[Temperature Range]   25.000   95.000   0.0
[Voltage Range]   1.500V   1.425V   1.575V
[GND_clamp]
|Voltage   I(typ)   I(min)   I(max)
-1.5V     -233mA     -234.1mA   -246mA
-1.252V   -154.7mA   -163.2mA   -159.2mA
-1.066V   -99.03mA   -112.2mA   -97.75mA
-1.004V   -81.93mA   -96.06mA   -79.21mA
-942mV    -66.64mA   -80.8mA    -63.44mA
-880mV    -55.17mA   -67.05mA   -53.47mA
-787mV    -47.71mA   -52.18mA   -47.82mA
-663mV    -42.67mA   -44.49mA   -42.72mA
-384mV    -32.97mA   -34.44mA   -32.77mA
701mV     -1.444mA   -345.1uA   -2.684mA
794mV     0A         0A         0A
1.5V      0A         0A         0A
[POWER_clamp]
|Voltage   I(typ)   I(min)   I(max)
-1.5V     275.1mA    282.5mA    283.7mA
-1.259V   176.1mA    190.1mA    177.2mA
-1.073V   104mA      122.1mA    100mA
-980mV    72.19mA    90.72mA    67.07mA
-918mV    55.68mA    71.97mA    51.94mA
-887mV    50.1mA     63.75mA    47.84mA
-825mV    44.43mA    51.02mA    43.98mA
-794mV    42.99mA    46.98mA    42.75mA
-701mV    39.68mA    41.2mA     39.41mA
694mV     1.795mA    616.3uA    2.696mA
787mV     0A         0A         0A
1.5V      0A         0A         0A
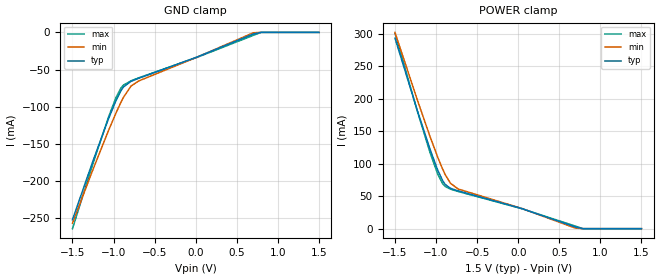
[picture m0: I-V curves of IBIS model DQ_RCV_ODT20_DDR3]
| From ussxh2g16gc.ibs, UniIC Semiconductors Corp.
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|   Model DQ_RCV_ODT20_DDR3
[Model] DQ_RCV_ODT20_DDR3
Model_type Input
Vinl =  0.615V
Vinh =  0.885V
C_comp   0.966pF   0.965pF   0.967pF
[Model Spec]
Vinh   0.885V   0.847V   0.922V
Vinl   0.615V   0.577V   0.652V
[Temperature Range]   25.000   95.000   0.0
[Voltage Range]   1.500V   1.425V   1.575V
[GND_clamp]
|Voltage   I(typ)   I(min)   I(max)
-1.5V     -252.3mA   -256.8mA   -264.3mA
-1.252V   -173.6mA   -185.1mA   -177.2mA
-1.066V   -117.7mA   -133.4mA   -115.5mA
-973mV    -92.5mA    -109.2mA   -88.44mA
-911mV    -78.68mA   -94.32mA   -75.08mA
-880mV    -73.54mA   -87.56mA   -70.98mA
-787mV    -65.87mA   -72.25mA   -65.22mA
-694mV    -61.79mA   -65.4mA    -61.21mA
19mV      -33.06mA   -33.19mA   -33.53mA
701mV     -2.159mA   -514.5uA   -4.016mA
794mV     0A         0A         0A
1.5V      0A         0A         0A
[POWER_clamp]
|Voltage   I(typ)   I(min)   I(max)
-1.5V     293.2mA    302mA      300.9mA
-1.228V   181.8mA    198.1mA    180.9mA
-1.073V   122mA      141.6mA    117mA
-980mV    90.12mA    110mA      84mA
-918mV    73.53mA    91.13mA    68.85mA
-887mV    67.91mA    82.82mA    64.73mA
-825mV    62.12mA    69.91mA    60.83mA
-732mV    58.2mA     61.06mA    57.23mA
43mV      30.98mA    31.1mA     30.76mA
694mV     2.693mA    925.4uA    4.041mA
787mV     0A         0A         0A
1.5V      0A         0A         0A
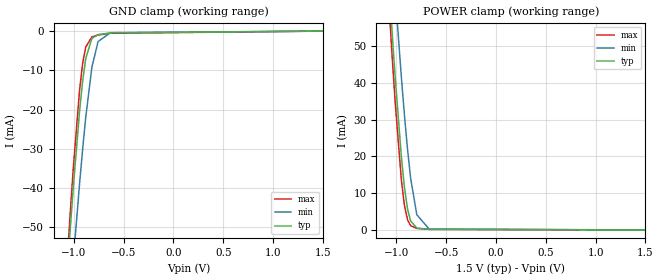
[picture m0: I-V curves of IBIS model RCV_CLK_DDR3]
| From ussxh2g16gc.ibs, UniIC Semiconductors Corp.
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|   Model RCV_CLK_DDR3
[Model] RCV_CLK_DDR3
Model_type Input
Vinl =  0.615V
Vinh =  0.885V
C_comp   0.694pF   0.694pF   0.694pF
[Model Spec]
Vinh   0.885V   0.847V   0.922V
Vinl   0.615V   0.577V   0.652V
[Temperature Range]   25.000   95.000   0.0
[Voltage Range]   1.500V   1.425V   1.575V
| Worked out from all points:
|   GND clamp passes 1 mA (typ) near -0.77 V on its own axis
|   POWER clamp passes 1 mA (typ) near -0.82 V on its own axis
[GND_clamp]
|Voltage   I(typ)   I(min)   I(max)
-1.5V     -234.6mA   -235.5mA   -250.7mA
-1.097V   -72.87mA   -89.24mA   -71.02mA
-1.066V   -61.4mA    -78.68mA   -58.39mA
-1.035V   -50.26mA   -68.31mA   -46.22mA
-1.004V   -39.59mA   -58.18mA   -34.71mA
-942mV    -20.46mA   -38.97mA   -15.1mA
-911mV    -12.75mA   -30.12mA   -8.227mA
-880mV    -6.991mA   -22.01mA   -4.072mA
-818mV    -1.855mA   -9.196mA   -1.477mA
-756mV    -905.3uA   -2.662mA   -1.011mA
-632mV    -459.6uA   -404.1uA   -556.8uA
1.5V      0A         0A         0A
[POWER_clamp]
|Voltage   I(typ)   I(min)   I(max)
-1.5V     266.1mA    275.5mA    274.2mA
-1.104V   80.17mA    101.8mA    75.27mA
-1.073V   66.81mA    89.05mA    61.13mA
-1.042V   53.89mA    76.58mA    47.56mA
-1.011V   41.58mA    64.45mA    34.82mA
-949mV    19.95mA    41.64mA    13.66mA
-918mV    11.61mA    31.29mA    6.692mA
-887mV    5.734mA    22mA       2.786mA
-856mV    2.465mA    14.14mA    1.163mA
-794mV    524.9uA    4.165mA    409.9uA
-670mV    155.5uA    244.3uA    188.6uA
1.5V      0A         0A         0A
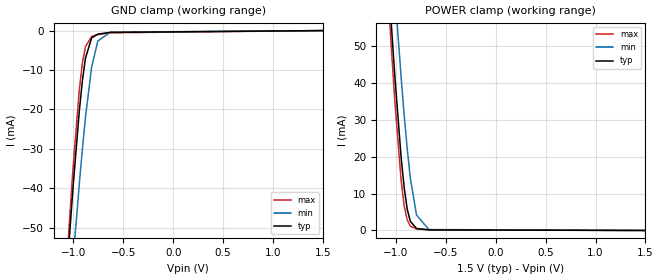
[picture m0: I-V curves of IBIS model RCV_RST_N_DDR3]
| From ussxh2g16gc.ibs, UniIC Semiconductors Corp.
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|   Model RCV_RST_N_DDR3
[Model] RCV_RST_N_DDR3
Model_type Input
Vinl =  0.615V
Vinh =  0.885V
C_comp   0.725pF   0.725pF   0.725pF
[Model Spec]
Vinh   0.885V   0.847V   0.922V
Vinl   0.615V   0.577V   0.652V
[Temperature Range]   25.000   95.000   0.0
[Voltage Range]   1.500V   1.425V   1.575V
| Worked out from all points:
|   GND clamp passes 1 mA (typ) near -0.77 V on its own axis
|   POWER clamp passes 1 mA (typ) near -0.82 V on its own axis
[GND_clamp]
|Voltage   I(typ)   I(min)   I(max)
-1.5V     -234.6mA   -235.5mA   -250.7mA
-1.097V   -72.88mA   -89.25mA   -71.02mA
-1.066V   -61.4mA    -78.68mA   -58.39mA
-1.035V   -50.27mA   -68.31mA   -46.22mA
-1.004V   -39.59mA   -58.18mA   -34.71mA
-942mV    -20.46mA   -38.97mA   -15.1mA
-911mV    -12.75mA   -30.12mA   -8.228mA
-880mV    -6.992mA   -22.01mA   -4.073mA
-818mV    -1.856mA   -9.196mA   -1.478mA
-756mV    -905.7uA   -2.662mA   -1.012mA
-632mV    -459.9uA   -404.2uA   -557.1uA
1.5V      0A         0A         0A
[POWER_clamp]
|Voltage   I(typ)   I(min)   I(max)
-1.5V     266.1mA    275.5mA    274.2mA
-1.104V   80.17mA    101.8mA    75.28mA
-1.073V   66.81mA    89.06mA    61.14mA
-1.042V   53.9mA     76.59mA    47.57mA
-1.011V   41.59mA    64.46mA    34.83mA
-949mV    19.96mA    41.64mA    13.66mA
-918mV    11.61mA    31.29mA    6.694mA
-887mV    5.735mA    22mA       2.787mA
-856mV    2.465mA    14.15mA    1.164mA
-794mV    525.1uA    4.165mA    410.2uA
-670mV    155.6uA    244.3uA    188.7uA
1.5V      0A         0A         0A
